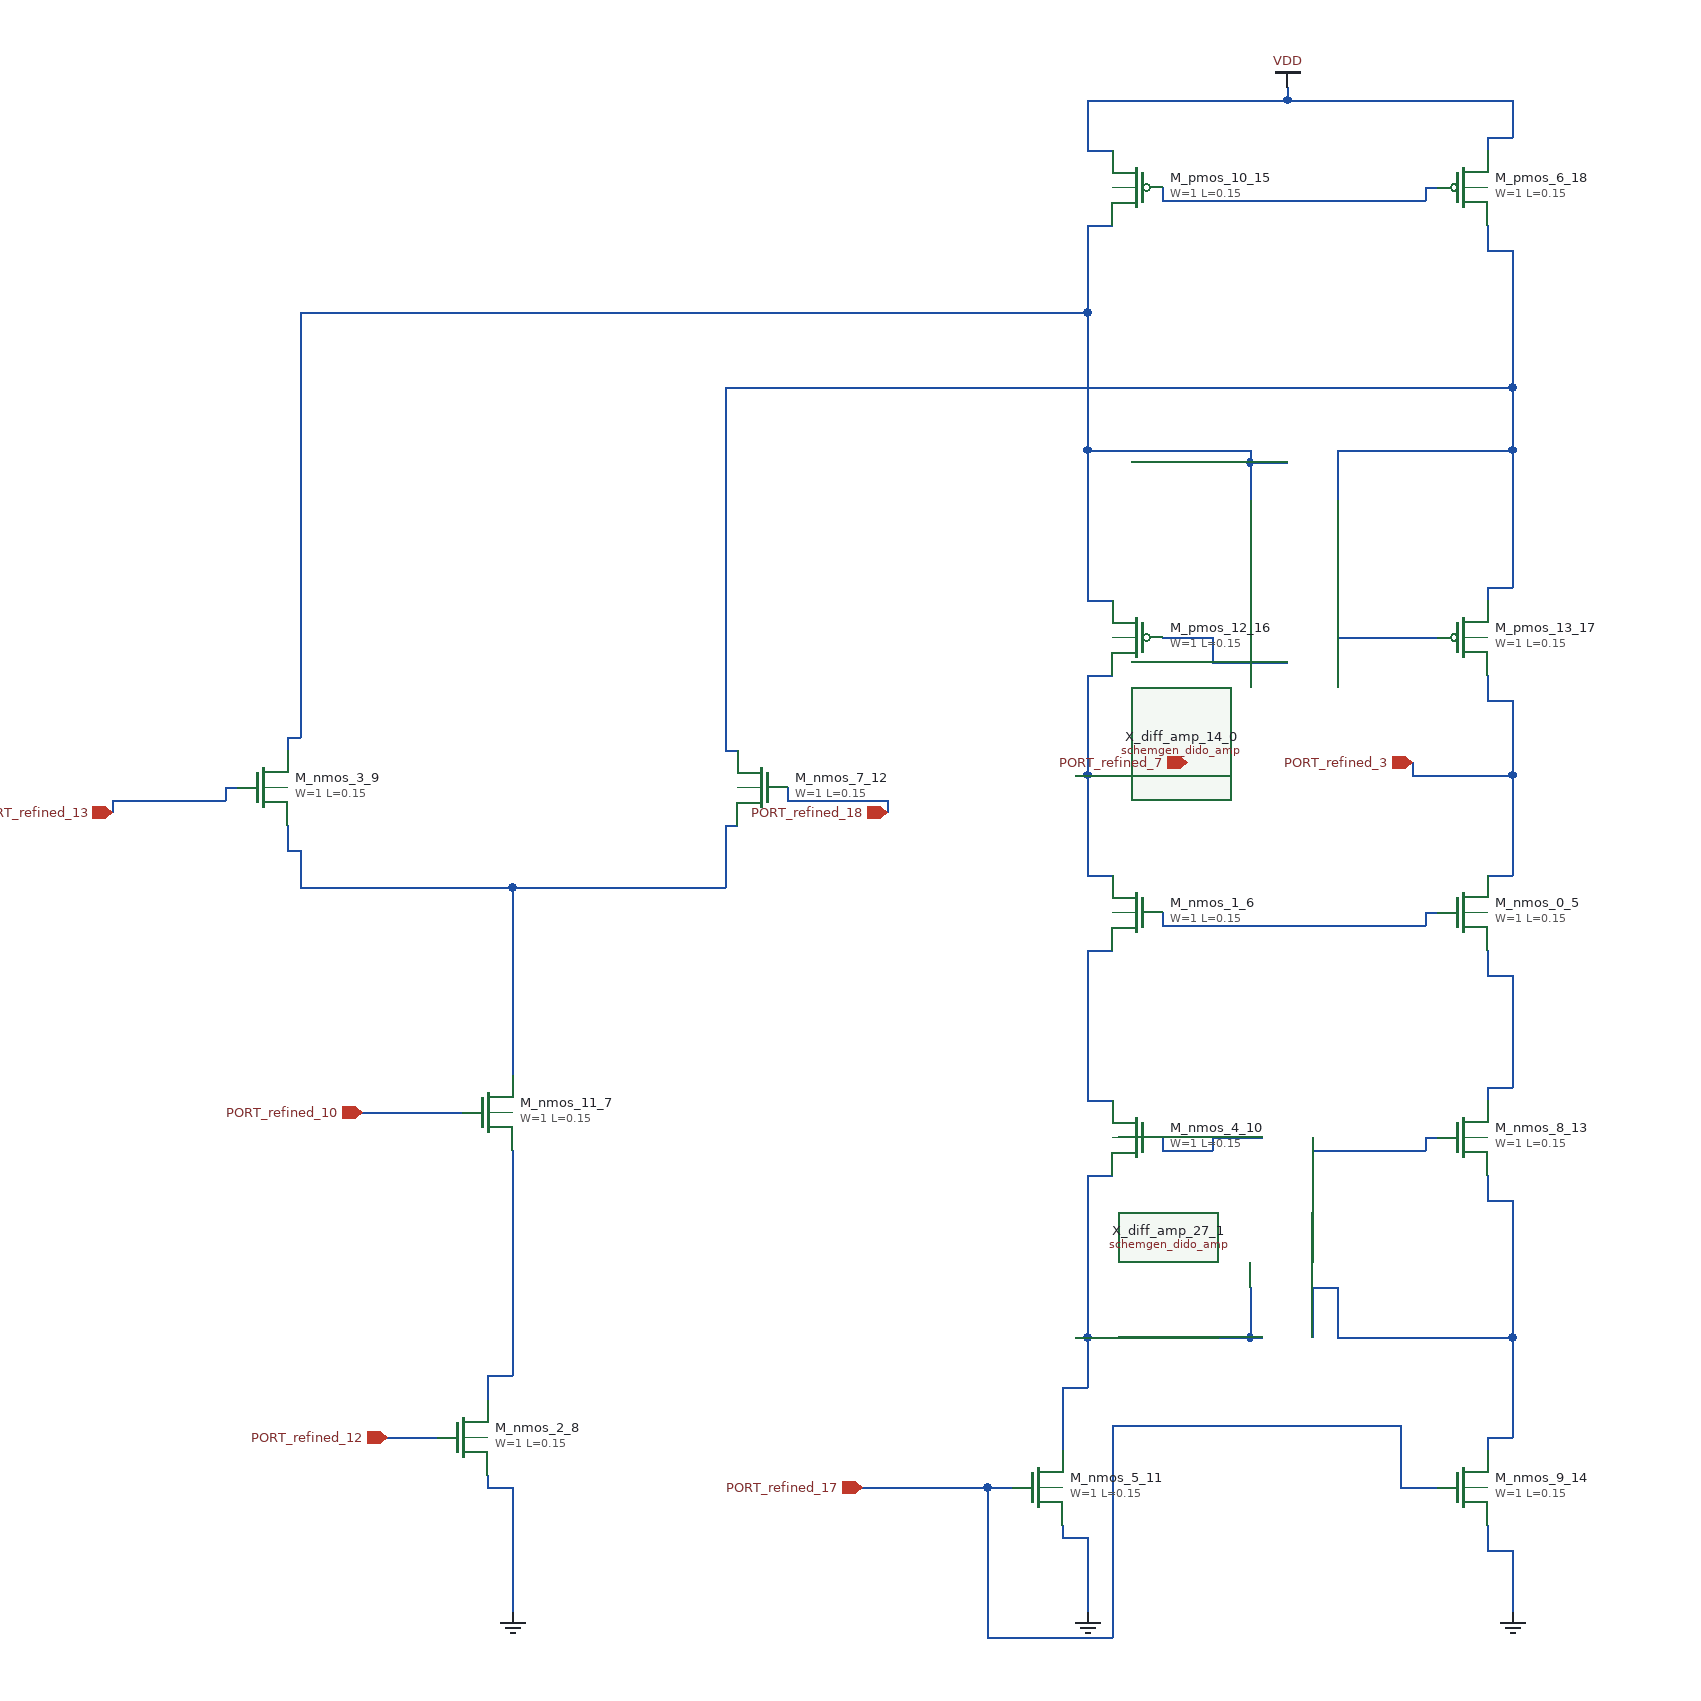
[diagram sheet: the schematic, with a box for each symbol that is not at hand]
v {xschem version=3.4.8 file_version=1.2}
G {}
K {}
V {}
S {}
E {}
C {schemgen_dido_amp.sym} 1040 480 3 1 {name="X_diff_amp_14_0"}
C {schemgen_dido_amp.sym} 1020 1020 3 0 {name="X_diff_amp_27_1"}
C {devices/gnd.sym} 1200 1320 0 0 {name="l_gnd_15_2" lab="GND"}
C {devices/gnd.sym} 400 1320 0 0 {name="l_gnd_16_3" lab="GND"}
C {devices/gnd.sym} 860 1320 0 0 {name="l_gnd_17_4" lab="GND"}
C {sky130_fd_pr/nfet3_01v8.sym} 1160 760 0 0 {name="M_nmos_0_5"
W=1
L=0.15
body=GND
nf=1
mult=1
ad="expr('int((@nf + 1)/2) * @W / @nf * 0.29')"
pd="expr('2*int((@nf + 1)/2) * (@W / @nf + 0.29)')"
as="expr('int((@nf + 2)/2) * @W / @nf * 0.29')"
ps="expr('2*int((@nf + 2)/2) * (@W / @nf + 0.29)')"
nrd="expr('0.29 / @W ')" nrs="expr('0.29 / @W ')"
sa=0 sb=0 sd=0
model=nfet_01v8
spiceprefix=X
}
C {sky130_fd_pr/nfet3_01v8.sym} 900 760 0 1 {name="M_nmos_1_6"
W=1
L=0.15
body=GND
nf=1
mult=1
ad="expr('int((@nf + 1)/2) * @W / @nf * 0.29')"
pd="expr('2*int((@nf + 1)/2) * (@W / @nf + 0.29)')"
as="expr('int((@nf + 2)/2) * @W / @nf * 0.29')"
ps="expr('2*int((@nf + 2)/2) * (@W / @nf + 0.29)')"
nrd="expr('0.29 / @W ')" nrs="expr('0.29 / @W ')"
sa=0 sb=0 sd=0
model=nfet_01v8
spiceprefix=X
}
C {sky130_fd_pr/nfet3_01v8.sym} 380 920 0 0 {name="M_nmos_11_7"
W=1
L=0.15
body=GND
nf=1
mult=1
ad="expr('int((@nf + 1)/2) * @W / @nf * 0.29')"
pd="expr('2*int((@nf + 1)/2) * (@W / @nf + 0.29)')"
as="expr('int((@nf + 2)/2) * @W / @nf * 0.29')"
ps="expr('2*int((@nf + 2)/2) * (@W / @nf + 0.29)')"
nrd="expr('0.29 / @W ')" nrs="expr('0.29 / @W ')"
sa=0 sb=0 sd=0
model=nfet_01v8
spiceprefix=X
}
C {sky130_fd_pr/nfet3_01v8.sym} 360 1180 0 0 {name="M_nmos_2_8"
W=1
L=0.15
body=GND
nf=1
mult=1
ad="expr('int((@nf + 1)/2) * @W / @nf * 0.29')"
pd="expr('2*int((@nf + 1)/2) * (@W / @nf + 0.29)')"
as="expr('int((@nf + 2)/2) * @W / @nf * 0.29')"
ps="expr('2*int((@nf + 2)/2) * (@W / @nf + 0.29)')"
nrd="expr('0.29 / @W ')" nrs="expr('0.29 / @W ')"
sa=0 sb=0 sd=0
model=nfet_01v8
spiceprefix=X
}
C {sky130_fd_pr/nfet3_01v8.sym} 200 660 0 0 {name="M_nmos_3_9"
W=1
L=0.15
body=GND
nf=1
mult=1
ad="expr('int((@nf + 1)/2) * @W / @nf * 0.29')"
pd="expr('2*int((@nf + 1)/2) * (@W / @nf + 0.29)')"
as="expr('int((@nf + 2)/2) * @W / @nf * 0.29')"
ps="expr('2*int((@nf + 2)/2) * (@W / @nf + 0.29)')"
nrd="expr('0.29 / @W ')" nrs="expr('0.29 / @W ')"
sa=0 sb=0 sd=0
model=nfet_01v8
spiceprefix=X
}
C {sky130_fd_pr/nfet3_01v8.sym} 900 940 0 1 {name="M_nmos_4_10"
W=1
L=0.15
body=GND
nf=1
mult=1
ad="expr('int((@nf + 1)/2) * @W / @nf * 0.29')"
pd="expr('2*int((@nf + 1)/2) * (@W / @nf + 0.29)')"
as="expr('int((@nf + 2)/2) * @W / @nf * 0.29')"
ps="expr('2*int((@nf + 2)/2) * (@W / @nf + 0.29)')"
nrd="expr('0.29 / @W ')" nrs="expr('0.29 / @W ')"
sa=0 sb=0 sd=0
model=nfet_01v8
spiceprefix=X
}
C {sky130_fd_pr/nfet3_01v8.sym} 820 1220 0 0 {name="M_nmos_5_11"
W=1
L=0.15
body=GND
nf=1
mult=1
ad="expr('int((@nf + 1)/2) * @W / @nf * 0.29')"
pd="expr('2*int((@nf + 1)/2) * (@W / @nf + 0.29)')"
as="expr('int((@nf + 2)/2) * @W / @nf * 0.29')"
ps="expr('2*int((@nf + 2)/2) * (@W / @nf + 0.29)')"
nrd="expr('0.29 / @W ')" nrs="expr('0.29 / @W ')"
sa=0 sb=0 sd=0
model=nfet_01v8
spiceprefix=X
}
C {sky130_fd_pr/nfet3_01v8.sym} 600 660 0 1 {name="M_nmos_7_12"
W=1
L=0.15
body=GND
nf=1
mult=1
ad="expr('int((@nf + 1)/2) * @W / @nf * 0.29')"
pd="expr('2*int((@nf + 1)/2) * (@W / @nf + 0.29)')"
as="expr('int((@nf + 2)/2) * @W / @nf * 0.29')"
ps="expr('2*int((@nf + 2)/2) * (@W / @nf + 0.29)')"
nrd="expr('0.29 / @W ')" nrs="expr('0.29 / @W ')"
sa=0 sb=0 sd=0
model=nfet_01v8
spiceprefix=X
}
C {sky130_fd_pr/nfet3_01v8.sym} 1160 940 0 0 {name="M_nmos_8_13"
W=1
L=0.15
body=GND
nf=1
mult=1
ad="expr('int((@nf + 1)/2) * @W / @nf * 0.29')"
pd="expr('2*int((@nf + 1)/2) * (@W / @nf + 0.29)')"
as="expr('int((@nf + 2)/2) * @W / @nf * 0.29')"
ps="expr('2*int((@nf + 2)/2) * (@W / @nf + 0.29)')"
nrd="expr('0.29 / @W ')" nrs="expr('0.29 / @W ')"
sa=0 sb=0 sd=0
model=nfet_01v8
spiceprefix=X
}
C {sky130_fd_pr/nfet3_01v8.sym} 1160 1220 0 0 {name="M_nmos_9_14"
W=1
L=0.15
body=GND
nf=1
mult=1
ad="expr('int((@nf + 1)/2) * @W / @nf * 0.29')"
pd="expr('2*int((@nf + 1)/2) * (@W / @nf + 0.29)')"
as="expr('int((@nf + 2)/2) * @W / @nf * 0.29')"
ps="expr('2*int((@nf + 2)/2) * (@W / @nf + 0.29)')"
nrd="expr('0.29 / @W ')" nrs="expr('0.29 / @W ')"
sa=0 sb=0 sd=0
model=nfet_01v8
spiceprefix=X
}
C {sky130_fd_pr/pfet3_01v8.sym} 900 180 0 1 {name="M_pmos_10_15"
W=1
L=0.15
body=VDD
nf=1
mult=1
ad="expr('int((@nf + 1)/2) * @W / @nf * 0.29')"
pd="expr('2*int((@nf + 1)/2) * (@W / @nf + 0.29)')"
as="expr('int((@nf + 2)/2) * @W / @nf * 0.29')"
ps="expr('2*int((@nf + 2)/2) * (@W / @nf + 0.29)')"
nrd="expr('0.29 / @W ')" nrs="expr('0.29 / @W ')"
sa=0 sb=0 sd=0
model=pfet_01v8
spiceprefix=X
}
C {sky130_fd_pr/pfet3_01v8.sym} 900 540 0 1 {name="M_pmos_12_16"
W=1
L=0.15
body=VDD
nf=1
mult=1
ad="expr('int((@nf + 1)/2) * @W / @nf * 0.29')"
pd="expr('2*int((@nf + 1)/2) * (@W / @nf + 0.29)')"
as="expr('int((@nf + 2)/2) * @W / @nf * 0.29')"
ps="expr('2*int((@nf + 2)/2) * (@W / @nf + 0.29)')"
nrd="expr('0.29 / @W ')" nrs="expr('0.29 / @W ')"
sa=0 sb=0 sd=0
model=pfet_01v8
spiceprefix=X
}
C {sky130_fd_pr/pfet3_01v8.sym} 1160 540 0 0 {name="M_pmos_13_17"
W=1
L=0.15
body=VDD
nf=1
mult=1
ad="expr('int((@nf + 1)/2) * @W / @nf * 0.29')"
pd="expr('2*int((@nf + 1)/2) * (@W / @nf + 0.29)')"
as="expr('int((@nf + 2)/2) * @W / @nf * 0.29')"
ps="expr('2*int((@nf + 2)/2) * (@W / @nf + 0.29)')"
nrd="expr('0.29 / @W ')" nrs="expr('0.29 / @W ')"
sa=0 sb=0 sd=0
model=pfet_01v8
spiceprefix=X
}
C {sky130_fd_pr/pfet3_01v8.sym} 1160 180 0 0 {name="M_pmos_6_18"
W=1
L=0.15
body=VDD
nf=1
mult=1
ad="expr('int((@nf + 1)/2) * @W / @nf * 0.29')"
pd="expr('2*int((@nf + 1)/2) * (@W / @nf + 0.29)')"
as="expr('int((@nf + 2)/2) * @W / @nf * 0.29')"
ps="expr('2*int((@nf + 2)/2) * (@W / @nf + 0.29)')"
nrd="expr('0.29 / @W ')" nrs="expr('0.29 / @W ')"
sa=0 sb=0 sd=0
model=pfet_01v8
spiceprefix=X
}
C {devices/ipin.sym} 300 1180 0 0 {name="p_port_19_19" lab="PORT_refined_12"}
C {devices/ipin.sym} 280 920 0 0 {name="p_port_20_20" lab="PORT_refined_10"}
C {devices/ipin.sym} 940 640 0 0 {name="p_port_22_21" lab="PORT_refined_7"}
C {devices/ipin.sym} 680 1220 0 0 {name="p_port_23_22" lab="PORT_refined_17"}
C {devices/ipin.sym} 1120 640 0 0 {name="p_port_24_23" lab="PORT_refined_3"}
C {devices/ipin.sym} 80 680 0 0 {name="p_port_25_24" lab="PORT_refined_13"}
C {devices/ipin.sym} 700 680 0 0 {name="p_port_26_25" lab="PORT_refined_18"}
C {devices/vdd.sym} 1020 100 0 0 {name="l_vdd_28_26" lab="VDD"}
N 570 630 580 630 {}
N 1180 500 1200 500 {}
N 1060 390 1200 390 {}
N 570 340 1200 340 {}
N 1180 230 1200 230 {}
N 570 630 570 340 {}
N 1060 430 1060 400 {}
N 1060 400 1060 390 {}
N 1180 510 1180 500 {}
N 1180 230 1180 210 {}
N 1200 500 1200 390 {}
N 1200 390 1200 340 {}
N 1200 340 1200 230 {}
N 220 620 230 620 {}
N 860 510 880 510 {}
N 990 400 1020 400 {}
N 860 390 990 390 {}
N 230 280 860 280 {}
N 860 210 880 210 {}
N 220 630 220 620 {}
N 230 620 230 280 {}
N 860 510 860 390 {}
N 860 390 860 280 {}
N 860 280 860 210 {}
N 990 430 990 400 {}
N 990 400 990 390 {}
N 280 920 360 920 {}
N 1060 540 1140 540 {}
N 1060 560 1060 540 {}
N 300 1180 340 1180 {}
N 80 670 170 670 {}
N 170 660 180 660 {}
N 80 680 80 670 {}
N 170 670 170 660 {}
N 840 1140 860 1140 {}
N 850 1100 860 1100 {}
N 860 1100 990 1100 {}
N 990 1100 1000 1100 {}
N 860 970 880 970 {}
N 840 1190 840 1140 {}
N 860 1140 860 1100 {}
N 860 1100 860 970 {}
N 990 1100 990 1060 {}
N 920 950 960 950 {}
N 960 940 1000 940 {}
N 920 950 920 940 {}
N 960 950 960 940 {}
N 960 560 1020 560 {}
N 920 540 960 540 {}
N 960 560 960 540 {}
N 780 1340 880 1340 {}
N 680 1220 780 1220 {}
N 780 1220 800 1220 {}
N 1110 1220 1140 1220 {}
N 880 1170 1110 1170 {}
N 780 1340 780 1220 {}
N 880 1340 880 1170 {}
N 1110 1220 1110 1170 {}
N 620 670 700 670 {}
N 620 670 620 660 {}
N 700 680 700 670 {}
N 1180 1180 1200 1180 {}
N 1060 1100 1200 1100 {}
N 1040 1060 1060 1060 {}
N 1180 990 1200 990 {}
N 1040 1100 1040 1060 {}
N 1060 1100 1060 1060 {}
N 1180 1190 1180 1180 {}
N 1180 990 1180 970 {}
N 1200 1180 1200 1100 {}
N 1200 1100 1200 990 {}
N 1180 1270 1200 1270 {}
N 840 1260 860 1260 {}
N 380 1220 400 1220 {}
N 380 1220 380 1210 {}
N 400 1320 400 1220 {}
N 840 1260 840 1250 {}
N 860 1320 860 1260 {}
N 1180 1270 1180 1250 {}
N 1200 1320 1200 1270 {}
N 1040 950 1130 950 {}
N 1130 940 1140 940 {}
N 1040 950 1040 940 {}
N 1130 950 1130 940 {}
N 860 150 880 150 {}
N 1180 140 1200 140 {}
N 860 110 1020 110 {}
N 1020 110 1200 110 {}
N 860 150 860 110 {}
N 1020 110 1020 100 {}
N 1180 150 1180 140 {}
N 1200 140 1200 110 {}
N 920 190 1130 190 {}
N 1130 180 1140 180 {}
N 920 190 920 180 {}
N 1130 190 1130 180 {}
N 1180 730 1200 730 {}
N 1120 650 1200 650 {}
N 1180 590 1200 590 {}
N 1120 650 1120 640 {}
N 1180 590 1180 570 {}
N 1200 730 1200 650 {}
N 1200 650 1200 590 {}
N 1180 900 1200 900 {}
N 1180 810 1200 810 {}
N 1180 910 1180 900 {}
N 1180 810 1180 790 {}
N 1200 900 1200 810 {}
N 920 770 1130 770 {}
N 1130 760 1140 760 {}
N 920 770 920 760 {}
N 1130 770 1130 760 {}
N 860 910 880 910 {}
N 860 790 880 790 {}
N 860 910 860 790 {}
N 860 730 880 730 {}
N 850 650 860 650 {}
N 860 650 940 650 {}
N 860 570 880 570 {}
N 860 730 860 650 {}
N 860 650 860 570 {}
N 940 650 940 640 {}
N 230 740 400 740 {}
N 400 740 570 740 {}
N 220 710 230 710 {}
N 570 690 580 690 {}
N 220 710 220 690 {}
N 230 740 230 710 {}
N 400 890 400 740 {}
N 570 740 570 690 {}
N 380 1130 400 1130 {}
N 380 1150 380 1130 {}
N 400 1130 400 950 {}
